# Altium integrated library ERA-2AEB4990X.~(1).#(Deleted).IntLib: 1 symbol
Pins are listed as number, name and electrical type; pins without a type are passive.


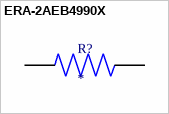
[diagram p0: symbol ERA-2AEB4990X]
## ERA-2AEB4990X
designator R?
MP: ERA-2AEB4990X
footprint RESC1005X40N
pins: 1, 2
